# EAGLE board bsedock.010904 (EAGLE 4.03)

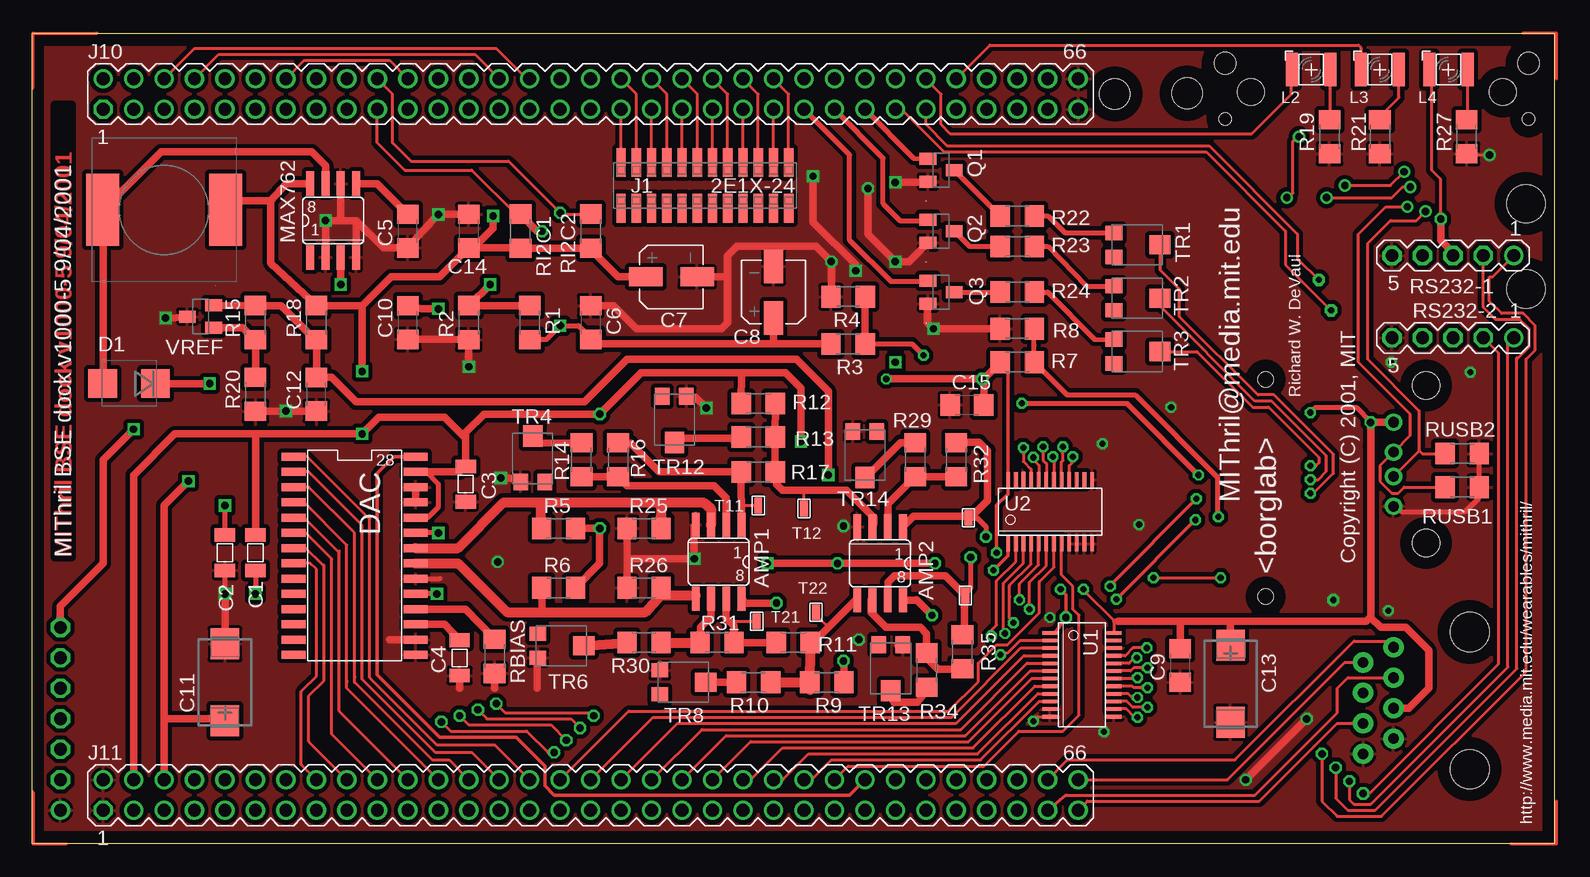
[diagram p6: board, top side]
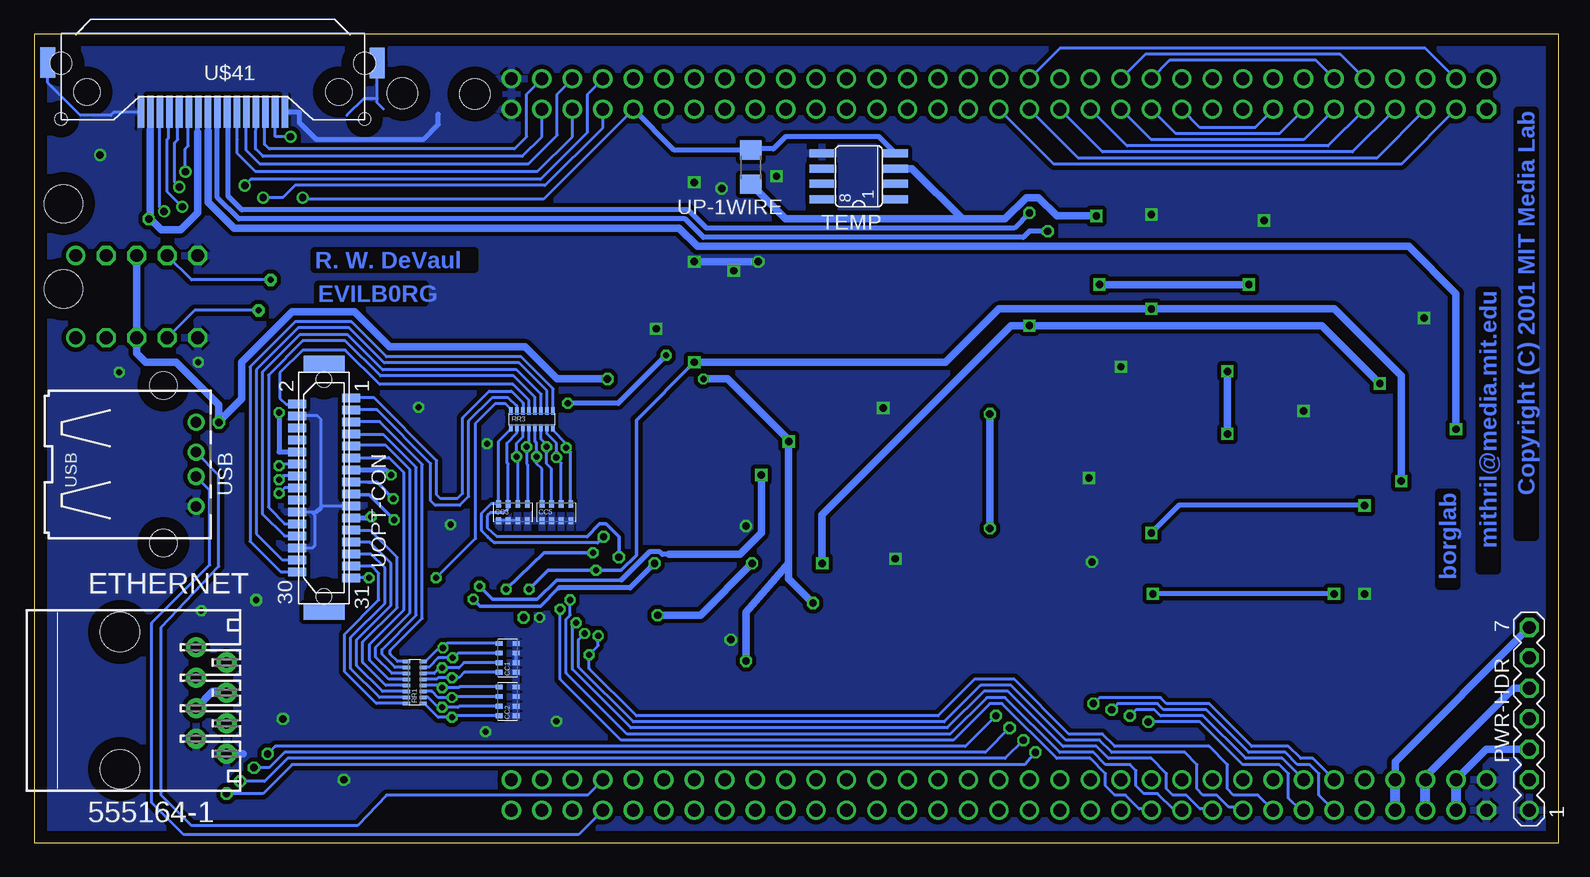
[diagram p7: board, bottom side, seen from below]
Size 126.98 x 67.49 mm. Coordinates in mm from the lower left corner, seen from the top.
Outline: 0,0 126.98,0 126.98,67.49 0,67.49 0,0
Copper layers used: Top, Bottom
Holes 3.17 mm at 124.58,46.19 124.58,53.3
Holes 2.54 mm at 90.29,62.45 96.32,62.51

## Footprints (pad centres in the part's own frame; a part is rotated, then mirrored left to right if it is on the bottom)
SO08 = smd 0.66 x 2.032: 1 -1.905,-3.073; 2 -0.635,-3.073; 3 0.635,-3.073; 4 1.905,-3.073; 5 1.905,3.073; 6 0.635,3.073; 7 -0.635,3.073; 8 -1.905,3.073
1206 = smd 1.143 x 1.702: 1 -1.473,0; 2 1.473,0
C1206 = smd 1.6 x 1.8: 1 -1.4,0; 2 1.4,0
PAN-LY-C = smd 1.6 x 2.8: P+ 0,-2.15; P- 0,2.15
CT7343 = smd 2.6 x 2.4: 1 -3.2,0; 2 3.2,0
ECJRV = smd 0.4 x 0.6: P$1 -1.2,-0.7; P$2 -0.4,-0.7; P$3 0.4,-0.7; P$4 1.2,-0.7; P$5 1.2,0.7; P$6 0.4,0.7; P$7 -0.4,0.7; P$8 -1.2,0.7
SMB = smd 2.4 x 2.4: 1 -2.2,0; 2 2.2,0
SMD-28 = smd 0.66 x 2.007: 1 -8.89,-5.08; 2 -7.62,-5.08; 3 -6.35,-5.08; 4 -5.08,-5.08; 5 -3.81,-5.08; 6 -2.54,-5.08; 7 -1.27,-5.08; 8 0,-5.08; 9 1.27,-5.08; 10 2.54,-5.08; 11 3.81,-5.08; 12 5.08,-5.08; 13 6.35,-5.08; 14 7.62,-5.08; 15 7.62,5.08; 16 6.35,5.08; 17 5.08,5.08; 18 3.81,5.08; 19 2.54,5.08; 20 1.27,5.08; 21 0,5.08; 22 -1.27,5.08; 23 -2.54,5.08; 24 -3.81,5.08; 25 -5.08,5.08; 26 -6.35,5.08; 27 -7.62,5.08; 28 -8.89,5.08
555164-1 = drill 0.889 pad 1.676 round: 1 -4.445,5.207; 2 -3.175,7.747; 3 -1.905,5.207; 4 -0.635,7.747; 5 0.635,5.207; 6 1.905,7.747; 7 3.175,5.207; 8 4.445,7.747 | hole 3.251: -5.715,-1.143; 5.715,-1.143
2E1X-24 = smd 0.762 x 2.388: P$1 -7.62,1.905; P$2 -7.62,-1.905; P$3 -6.35,1.905; P$4 -6.35,-1.905; P$5 -5.08,1.905; P$6 -5.08,-1.905; P$7 -3.81,1.905; P$8 -3.81,-1.905; P$9 -2.54,1.905; P$10 -2.54,-1.905; P$11 -1.27,1.905; P$12 -1.27,-1.905; P$13 0,1.905; P$14 0,-1.905; P$15 1.27,1.905; P$16 1.27,-1.905; P$17 2.54,1.905; P$18 2.54,-1.905; P$19 3.81,1.905; P$20 3.81,-1.905; P$21 5.08,1.905; P$22 5.08,-1.905; P$23 6.35,1.905; P$24 6.35,-1.905
BSEHDR = drill 1.067 pad 1.6 octagon: 1 -41.91,-1.27 | drill 1.067 pad 1.6 round: 2 -41.91,1.27; 3 -39.37,-1.27; 4 -39.37,1.27; 5 -36.83,-1.27; 6 -36.83,1.27; 7 -34.29,-1.27; 8 -34.29,1.27; 9 -31.75,-1.27; 10 -31.75,1.27; 11 -29.21,-1.27; 12 -29.21,1.27; 13 -26.67,-1.27; 14 -26.67,1.27; 15 -24.13,-1.27; 16 -24.13,1.27; 17 -21.59,-1.27; 18 -21.59,1.27; 19 -19.05,-1.27; 20 -19.05,1.27; 21 -16.51,-1.27; 22 -16.51,1.27; 23 -13.97,-1.27; 24 -13.97,1.27; 25 -11.43,-1.27; 26 -11.43,1.27; 27 -8.89,-1.27; 28 -8.89,1.27; 29 -6.35,-1.27; 30 -6.35,1.27; 31 -3.81,-1.27; 32 -3.81,1.27; 33 -1.27,-1.27; 34 -1.27,1.27; 35 1.27,-1.27; 36 1.27,1.27; 37 3.81,-1.27; 38 3.81,1.27; 39 6.35,-1.27; 40 6.35,1.27; 41 8.89,-1.27; 42 8.89,1.27; 43 11.43,-1.27; 44 11.43,1.27; 45 13.97,-1.27; 46 13.97,1.27; 47 16.51,-1.27; 48 16.51,1.27; 49 19.05,-1.27; 50 19.05,1.27; 51 21.59,-1.27; 52 21.59,1.27; 53 24.13,-1.27; 54 24.13,1.27; 55 26.67,-1.27; 56 26.67,1.27; 57 29.21,-1.27; 58 29.21,1.27; 59 31.75,-1.27; 60 31.75,1.27; 61 34.29,-1.27; 62 34.29,1.27; 63 36.83,-1.27; 64 36.83,1.27; 65 39.37,-1.27; 66 39.37,1.27
D124C = smd 2.743 x 5.994: P$1 -5.131,0; P$2 5.131,0
L62711CT = smd 1 x 2.8: P$1 -1.6,0; P$2 1.6,0
MA07-1 = drill 1.067 pad 1.6 round: 1 -7.62,0 | drill 1.067 pad 1.6 octagon: 2 -5.08,0; 3 -2.54,0; 4 0,0; 5 2.54,0; 6 5.08,0; 7 7.62,0
SOT23 = smd 1 x 1.4: 1 -0.95,-1.1; 2 0.95,-1.1; 3 0,1.1
R1206 = smd 1.6 x 1.803: 1 -1.422,0; 2 1.422,0
EXB2HV = smd 0.294 x 0.6: P$1 -1.75,-0.7; P$2 -1.25,-0.7; P$3 -0.75,-0.7; P$4 -0.25,-0.7; P$5 0.25,-0.7; P$6 0.75,-0.7; P$7 1.25,-0.7; P$8 1.75,-0.7; P$9 1.75,0.7; P$10 1.25,0.7; P$11 0.75,0.7; P$12 0.25,0.7; P$13 -0.25,0.7; P$14 -0.75,0.7; P$15 -1.25,0.7; P$16 -1.75,0.7
MA05-1 = drill 1.067 pad 1.6 round: 1 -5.08,0 | drill 1.067 pad 1.6 octagon: 2 -2.54,0; 3 0,0; 4 2.54,0; 5 5.08,0
TEST = smd 0.66 x 1.27: P$1 0,0
P7JSMTPO = smd 1.194 x 1.397: 1 -1,-1.854; 3 1,-1.854 | smd 1.6 x 1.778: 2 0,1.98
QSOP24 = smd 0.305 x 1.27: P$1 0.838,-0.711; P$2 1.473,-0.711; P$3 2.108,-0.711; P$4 2.743,-0.711; P$5 3.378,-0.711; P$6 4.013,-0.711; P$7 4.648,-0.711; P$8 5.283,-0.711; P$9 5.918,-0.711; P$10 6.553,-0.711; P$11 7.188,-0.711; P$12 7.823,-0.711; P$13 7.823,4.623; P$14 7.188,4.623; P$15 6.553,4.623; P$16 5.918,4.623; P$17 5.283,4.623; P$18 4.648,4.623; P$19 4.013,4.623; P$20 3.378,4.623; P$21 2.743,4.623; P$22 2.108,4.648; P$23 1.473,4.623; P$24 0.838,4.623
HRS3500 = smd 0.55 x 2.7: P$1 6,1.35; P$2 5.2,1.35; P$3 4.4,1.35; P$4 3.6,1.35; P$5 2.8,1.35; P$6 2,1.35; P$7 1.2,1.35; P$8 0.4,1.35; P$9 -0.4,1.35; P$10 -1.2,1.35; P$11 -2,1.35; P$12 -2.8,1.35; P$13 -3.6,1.35; P$14 -4.4,1.35; P$15 -5.2,1.35; P$16 -6,1.35 | smd 1.27 x 2.54: P_GND1 -13.7,-2.7; P_GND2 13.76,-2.74 | hole 2.2: -10.5,-0.3; 10.5,-0.3 | hole 1.8: -12.65,-2.7; 12.65,-2.7 | hole 1: -12.65,1.95; 12.65,1.95
DF9-31S = smd 0.7 x 1.5: 1 -7.5,2.25; 2 -7,-2.25; 3 -6.5,2.25; 4 -6,-2.25; 5 -5.5,2.25; 6 -5,-2.25; 7 -4.5,2.25; 8 -4,-2.25; 9 -3.5,2.25; 10 -3,-2.25; 11 -2.5,2.25; 12 -2,-2.25; 13 -1.5,2.25; 14 -1,-2.25; 15 -0.5,2.25; 16 0,-2.25; 17 0.5,2.25; 18 1,-2.25; 19 1.5,2.25; 20 2,-2.25; 21 2.5,2.25; 22 3,-2.25; 23 3.5,2.25; 24 4,-2.25; 25 4.5,2.25; 26 5,-2.25; 27 5.5,2.25; 28 6,-2.25; 29 6.5,2.25; 30 7,-2.25; 31 7.5,2.25 | smd 1.3 x 3.4: M1 -10.35,0; M2 10.35,0 | hole 1.27: 9.05,0; -9.05,0
USB = drill 0.889 pad 1.422 round: 1 -3.505,12.7; 2 -1.016,12.7; 3 1.016,12.7; 4 3.505,12.7 | hole 2.261: -6.566,9.982; 6.566,9.982

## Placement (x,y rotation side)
AMP1  AD8042AR  [SO08]  57.27,23.46 180 top
AMP2  EL2250CS  [SO08]  70.73,23.33 180 top
C1  0.1uF  [1206]  18.66,24.22 90 top
C2  0.1uF  [1206]  16.12,24.22 270 top
C3  0.1uF  [1206]  36.19,29.93 270 top
C4  0.1uF  [1206]  35.68,15.46 270 top
C5  0.1uF  [C1206]  31.36,51.02 90 top
C6  0.1uF  [C1206]  46.6,43.4 270 top
C7  33uF  [PAN-LY-C]  53.34,47.21 270 top
C8  33uF  [PAN-LY-C]  61.84,45.94 0 top
C9  0.1uF  [C1206]  95.75,14.82 90 top
C10  0.1uF  [C1206]  31.36,43.4 90 top
C11  10uF  [CT7343]  16.12,13.42 90 top
C12  0.1uF  [C1206]  23.74,37.43 90 top
C13  10uF  [CT7343]  99.94,13.3 270 top
C14  0.1uF  [C1206]  36.44,51.02 270 top
C15  0.1uF  [C1206]  77.97,36.54 0 top
CC1  10pF  [ECJRV]  87.56,15.46 90 bottom
CC2  10pF  [ECJRV]  87.56,11.84 90 bottom
CC3  10pF  [ECJRV]  87.12,27.58 0 bottom
CC5  10pF  [ECJRV]  83.5,27.58 0 bottom
D1  MBRS130LT3  [SMB]  8.12,38.32 180 top
DAC  THS5641IDW  [SMD-28]  26.92,23.33 270 top
ETHERNET  555164-1  [555164-1]  118.74,11.9 270 bottom
J1  2E1X-24  [2E1X-24]  56.76,54.83 0 top
J10  BSEHDR  [BSEHDR]  47.87,62.45 0 top
J11  BSEHDR  [BSEHDR]  47.87,4.03 0 top
L1  18uH  [D124C]  11.04,52.79 180 top
L2  L628111CT-ND  [L62711CT]  106.67,64.48 0 top
L3  L628111CT-ND  [L62711CT]  112.39,64.48 0 top
L4  L628111CT-ND  [L62711CT]  118.11,64.48 0 top
MAX762  MAX762  [SO08]  25.14,51.91 0 top
PWR-HDR  MA07-1  [MA07-1]  2.41,10.38 90 bottom
Q1  2N7002  [SOT23]  75.81,56.1 270 top
Q2  2N7002  [SOT23]  75.81,51.02 270 top
Q3  2N7002  [SOT23]  75.81,45.94 270 top
R1  1.267M  [R1206]  41.52,43.4 270 top
R2  200K  [R1206]  36.44,43.4 90 top
R3  16.4k  [R1206]  68.07,41.62 180 top
R4  23.6k  [R1206]  68.07,45.55 0 top
R5  2.65k  [R1206]  43.94,26.25 0 top
R6  2.65k  [R1206]  43.94,21.3 0 top
R7  20K  [R1206]  82.16,40.09 180 top
R8  20K  [R1206]  82.16,42.89 0 top
R9  2.52k  [R1206]  66.29,13.42 0 top
R10  2.0k  [R1206]  60.19,13.42 0 top
R11  2.90k  [R1206]  63.49,16.73 180 top
R12  7.06k  [R1206]  60.57,36.66 180 top
R13  2.0k  [R1206]  60.57,33.87 0 top
R14  2k  [R1206]  45.84,31.97 270 top
R15  43k  [R1206]  18.66,43.4 90 top
R16  3.78k  [R1206]  48.89,31.97 90 top
R17  4.05k  [R1206]  60.57,30.95 180 top
R18  47k  [R1206]  23.74,43.4 90 top
R19  2.2k  [R1206]  108.2,58.89 90 top
R20  30k  [R1206]  18.66,37.43 90 top
R21  2.2k  [R1206]  112.39,58.89 90 top
R22  4.7 ohm  [R1206]  82.16,52.29 180 top
R23  4.7 ohm  [R1206]  82.16,49.75 180 top
R24  4.7 ohm  [R1206]  82.16,45.94 180 top
R25  49  [R1206]  51.05,26.25 0 top
R26  49  [R1206]  51.05,21.3 0 top
R27  2.2k  [R1206]  119.63,58.89 90 top
R29  2k  [R1206]  73.66,31.97 270 top
R30  2k  [R1206]  51.05,16.73 0 top
R31  3.78k  [R1206]  57.14,16.73 0 top
R32  6.3k  [R1206]  77.08,31.97 90 top
R34  2k  [R1206]  74.61,14.44 90 top
R35  6.3k  [R1206]  77.59,15.96 90 top
RBIAS  2k  [R1206]  38.6,15.58 90 top
RI2C1  5k  [R1206]  40.76,51.02 270 top
RI2C2  5k  [R1206]  46.6,51.02 270 top
RR1  10  [EXB2HV]  95.31,13.42 90 bottom
RR3  10  [EXB2HV]  85.53,35.33 0 bottom
RS232-1  MA05-1  [MA05-1]  118.49,48.98 180 top
RS232-2  MA05-1  [MA05-1]  118.49,42.13 180 top
RUSB1  15K  [R1206]  119.25,29.68 180 top
RUSB2  15K  [R1206]  119.25,32.47 180 top
T1  TEST  [TEST]  60.57,28.16 0 top
T2  TEST  [TEST]  60.45,18.5 0 top
T3  TEST  [TEST]  65.4,19.27 0 top
T4  TEST  [TEST]  64.38,27.9 0 top
T5  TEST  [TEST]  78.1,27.14 0 top
T6  TEST  [TEST]  77.85,20.66 0 top
TEMP  DS1820  [SO08]  58.29,55.59 90 bottom
TR1  200 POT  [P7JSMTPO]  92.07,49.87 270 top
TR2  200 POT  [P7JSMTPO]  92.07,45.43 270 top
TR3  200 POT  [P7JSMTPO]  92.07,40.98 270 top
TR4  200 POT  [P7JSMTPO]  41.78,31.97 0 top
TR6  200 POT  [P7JSMTPO]  44.06,16.47 270 top
TR8  200 POT  [P7JSMTPO]  54.22,13.42 270 top
TR12  200 POT  [P7JSMTPO]  53.59,35.4 180 top
TR13  200 POT  [P7JSMTPO]  71.62,14.69 180 top
TR14  200 POT  [P7JSMTPO]  69.46,32.47 180 top
U1  74LVX3245QSCF  [QSOP24]  85.59,18.38 270 top
U2  74LVX3245QSCF  [QSOP24]  80.58,25.68 0 top
U$41  HRS3500R  [HRS3500]  112.14,62.32 180 bottom
UOPT-CON  DF9-31S  [DF9-31S]  102.86,29.62 270 bottom
UP-1WIRE  5k  [R1206]  67.31,56.35 270 bottom
USB  USB-87531  [USB]  126.23,31.59 270 bottom
VREF  4041CIM  [SOT23]  14.09,43.9 90 top

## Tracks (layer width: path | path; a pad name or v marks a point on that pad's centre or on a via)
1WIRE  (via drill 0.61 pad 1.02)
  Top 0.254: v105.66,58.89 105.53,58.89 105.15,58.51 105.15,54.19 104.77,53.81 v104.64,53.81
  Bottom 0.254: v105.66,58.89 106.93,58.89 U$41.P$15 | v104.64,53.81 104.77,53.68 84.58,53.68 J10.57
  Bottom 0.406: J10.57 73.68,57.77 UP-1WIRE.1 67.2,57.87 65.4,57.87 64.38,58.89 56.61,58.89 TEMP.4
+2V  (via drill 0.51 pad 0.3, 0.61 pad 1.02)
  Top 0.305: v97.09,28.73 89.91,21.49 v89.91,21.43
  Top 0.61: v66.42,30.7 66.42,37.68 63.75,40.35 49.65,40.35 46.1,36.79 27.05,36.79 25.01,38.82 C12.2 R18.1 23.64,41.97 20.82,44.79 18.66,44.79 | 18.66,44.79 R15.2 | VREF.2 18.66,44.79
  Bottom 0.305: 78.1,21.93 83.5,21.93 85.08,20.35 88.83,20.35 v89.91,21.43 | UOPT-CON.15 99.18,30.09 98.45,30.09 v97.09,28.73
  Bottom 0.406: 74.1,24.09 74.67,24.09 74.86,24.28 75.75,24.28 78.1,21.93
  Bottom 0.61: v66.42,30.7 66.42,25.87 68.19,24.09 74.1,24.09
+3V  (via drill 0.51 pad 0.3, 0.61, 0.61 pad 1.02)
  Top 0.254: 81.4,24.98 U2.P$1
  Top 0.305: U1.P$1 85.33,17.54 v86.23,18.82 86.23,20.73 v85.78,21.17 | v80.19,22.76 81.4,23.96 81.4,24.98
  Top 0.61: J11.6 11.04,10.38 | 11.04,10.38 11.04,28.16 v13.08,30.19 | v33.9,44.54 32.51,44.54 C10.2 | C11.1 16.12,10.38 11.04,10.38
  Bottom 0.305: v85.78,21.17 84.2,22.76 v80.19,22.76 78.1,22.76 76.83,24.03 76.83,35.27 v72,40.09
  Bottom 0.61: v13.08,30.19 13.08,38.95 18.66,44.54 v33.9,44.54 46.6,44.54 51.05,40.09 v72,40.09 | PWR-HDR.5 3.68,12.92 11.04,5.55 J11.6
  Bottom 0.813: J11.5 J11.6
+5V  (via drill 0.51 pad 0.3, 0.61, 0.61 pad 1.02)
  Top 0.254: 116.58,64.4 L4.P$1 116.5,64.02 116.45,63.97 116.45,64.22 116.71,63.97 116.71,56.1 117.47,55.33 v117.47,52.03 | v87.69,21.17 87.69,21.11 90.22,18.58 U1.P$24
  Top 0.305: 81.4,30.32 U2.P$24 | 81.4,30.32 81.4,29.11 80.45,28.16 v80.45,24.22 | 80.77,40.09 80.77,40.22 81.4,39.59 81.4,30.32
  Top 0.406: DAC.24 33.02,27.14 33.9,28.03 33.9,29.93 32.89,30.95 DAC.27 31.87,30.95 | v106.61,35.9 106.99,36.28 110.5,36.28 111.63,35.15 111.64,35.14 | 90.55,18.5 90.29,18.5
  Top 0.61: ETHERNET.5 114.8,11.27 116.45,12.92 116.45,16.09 114.55,18 112.45,18 111.63,18.82 111.63,18.89 | 59.18,39.2 50.8,39.2 v47.37,35.78 37.71,35.78 36.19,34.25 36.19,33.74 | 59.18,39.2 62.86,39.2 64.13,37.94 v64.13,33.49 | 18.66,34.12 v27.55,34.12 28.95,35.52 34.41,35.52 36.19,33.74 | C14.2 34.03,47.21 29.97,47.21 27.55,44.79 | 27.55,44.79 23.74,44.79 | MAX762.8 23.26,54.95 21.2,54.95 19.93,53.56 | C14.2 38.86,49.62 40,49.62 RI2C1.2 RI2C2.2 | R5.2 v47.37,26.25 47.37,23.33 R6.2 | 59.18,39.2 R12.2 | 67.81,12.89 67.81,12.79 | 67.81,12.89 R9.2 | v67.69,15.2 67.81,12.89 | RI2C2.2 46.6,49.62 | 23.74,44.79 R18.2 | 23.74,44.79 19.93,48.35 19.93,53.56 | L1.P$1 16.94,53.56 19.93,53.56 | DAC.27 35.68,30.95 36.19,31.46 C3.1 36.19,33.74 | J11.4 8.5,30.7 11.93,34.12 18.66,34.12 | v27.55,39.33 27.55,44.79 | 18.66,34.12 C1.2 | RI2C2.2 46.6,49.49 48.89,47.21 C7.P+ | v38.48,52.29 38.48,51.27 36.95,49.75 36.44,49.75 C14.2 | v117.47,52.03 117.47,50.25 118.49,49.24 RS232-1.3 | v62.1,20.03 59.3,20.03 59.3,20.28 59.2,20.38 AMP1.8 | R7.2 80.77,40.09 79.37,38.7 v79.24,38.7 | v71.24,38.7 v79.24,38.7 | 111.63,33.11 111.63,18.89 | 111.63,33.11 111.63,33.12 | v111.63,35.08 111.63,34.76 111.63,33.11 | v111.63,35.08 111.63,35.15 | USB.1 v111.63,35.08 | C15.2 79.37,38.57 v79.24,38.7 | 99.94,18.5 C13.1 | 95.75,18.5 C9.2 | 99.94,18.5 111.25,18.5 111.63,18.89 | 95.75,18.5 90.55,18.5 | 99.94,18.5 95.75,18.5
  Bottom 0.254: v64.13,33.49 64.07,33.55
  Bottom 0.305: v80.45,24.22 84.51,24.22 v87.69,21.17
  Bottom 0.406: 117.34,59.45 U$41.P$2 | v117.47,52.03 117.34,52.03 | U$41.P$7 113.38,60.92 113.41,60.92 113.41,59.27 | UOPT-CON.10 106.47,32.62 106.61,32.6 v106.61,35.9
  Bottom 0.61: v64.13,33.49 64.13,23.33 | v27.55,34.12 v27.55,39.33 | v47.37,35.78 v47.37,26.25 | 117.34,59.45 117.34,52.03 116.45,51.14 114.8,51.14 113.41,52.54 113.41,59.27 | v67.69,15.2 67.69,19.27 64.13,23.33 | v38.48,52.29 41.78,52.29 43.3,53.81 44.32,53.81 46.1,52.03 49.65,52.03 | 49.65,52.03 64.38,52.03 67.18,54.83 67.2,54.83 UP-1WIRE.2 | ETHERNET.4 111.12,12.66 112.14,12.66 ETHERNET.5 | RS232-1.3 RS232-2.3 118.49,40.86 117.72,40.09 115.18,40.09 111.63,36.54 111.63,35.14 | 64.13,23.33 64.13,22.06 v62.1,20.03 | TEMP.3 53.84,56.22 49.65,52.03 | J11.4 5.96,7.84 PWR-HDR.3 | v71.24,38.7 69.21,38.7 64.07,33.55 | 111.63,35.14 v111.63,35.08 | v79.24,38.7 83.43,38.7 86.1,41.36 97.4,41.36 100.33,44.29 105.53,44.29 109.72,40.09 109.72,37.05 111.63,35.14
  Bottom 0.813: J11.4 J11.3
+6.5VREF  (via drill 0.51 pad 0.3)
  Top 0.406: R3.1 73.4,41.62 v74.35,40.67 | v82.55,36.66 91.31,36.66 v97.28,30.7
  Top 0.61: R3.1 R4.2
  Bottom 0.406: 74.29,40.73 v74.35,40.67 78.35,36.66 v82.55,36.66 | UOPT-CON.13 100.58,31.08 97.66,31.08 v97.28,30.7
+11V  (via drill 0.51 pad 0.3, 0.61, 0.61 pad 1.02)
  Top 0.305: v90.42,20.35 v97.02,26.95
  Top 0.406: C6.2 46.6,42.13 45.59,43.14 v44.06,43.14 42.9,41.97 R1.2
  Top 0.61: D1.1 v14.85,38.32 | 61.84,41.62 C8.P+ | 61.84,41.62 R3.2 | C6.2 46.98,41.62 61.84,41.62 | v75.31,23.33 v67.18,23.33 v61.34,23.33 | v75.05,19.01 73.78,20.28 73.76,20.26 AMP2.8
  Bottom 0.305: 83.31,21.3 84.83,19.77 89.85,19.77 v90.42,20.35 | UOPT-CON.17 100.06,29.12 100.07,29.11 100.01,29.05 99.12,29.05 v97.02,26.95
  Bottom 0.406: v75.31,23.33 77.34,21.3 83.31,21.3
  Bottom 0.61: v61.34,23.33 61.34,27.39 45.59,43.14 v44.06,43.14 19.68,43.14 v14.85,38.32 | v75.05,19.01 71.5,19.01 v67.18,23.33
BLINKY1
  Top 0.254: L3.P$1 110.79,66.33 110.61,66.51 79.88,66.51 J10.58
BLINKY2
  Top 0.254: J10.56 75.81,62.45 75.81,59.91 76.58,59.14 101.72,59.14 105.02,62.45 105.02,64.43 L2.P$1
BSE_B
  Top 0.406: Q1.1 73.53,57.09 J10.51
BSE_G
  Top 0.406: Q2.1 74.78,51.91 72.39,51.91 70.99,53.3 70.99,57.11 J10.49
BSE_INIT
  Top 0.254: J11.50 68.07,6.44 79.37,6.44 82.29,9.36 85.97,9.36 87.31,10.69 87.31,19.01 86.8,19.52 86.8,21.43 85.86,22.37 U2.P$8 85.85,24.98
BSE_PDR
  Top 0.254: J11.32 49.78,11.01 76.45,11.01 78.93,13.49 78.93,15.01 80.45,16.54 81.34,16.54 84,19.2 84,19.84 | 85.21,24.98 U2.P$7 85.22,23.02 84,21.81 84,19.84 | 84,19.84 84,19.9
BSE_R
  Top 0.406: Q3.1 74.78,46.83 71.62,46.83 68.19,50.25 68.19,57.37 J10.47
BSEDCIN  (via drill 0.61 pad 1.02)
  Top 0.61: v8.5,34.51 5.96,31.97 5.96,23.33 2.41,19.77 PWR-HDR.7
  Bottom 0.406: 112.52,59.4 112.54,60.94 U$41.P$8
  Bottom 0.61: v8.5,34.51 8.5,45.81 12.44,49.75 71.75,49.75 73.27,51.27 110.36,51.27 112.52,53.43 112.52,59.4 | PWR-HDR.7 13.58,6.82 J11.8
  Bottom 0.813: J11.7 J11.8
DAC0
  Top 0.254: DAC.8 23.24,23.33 23.74,22.82 23.74,13.93 22.47,12.66 22.47,6.57 J11.16
DAC1
  Top 0.254: 24.38,23.08 22.73,24.73 21.97,24.73 DAC.7 | J11.18 23.11,8.47 23.11,12.28 24.38,13.55 24.38,23.08 | 24.38,23.08 24.38,23.2
DAC2
  Top 0.254: J11.20 25.01,9.11 25.01,23.71 22.85,25.87 DAC.6
DAC3
  Top 0.254: 25.65,24.22 22.73,27.14 DAC.5 | 25.65,24.22 25.65,24.35 | J11.22 25.65,11.01 25.65,24.22
DAC4
  Top 0.254: 26.28,13.55 26.28,24.85 22.73,28.41 DAC.4 21.59,28.41 | 26.28,13.55 26.28,13.42 | J11.24 26.28,12.92 26.28,13.55
DAC5
  Top 0.254: J11.26 34.79,6.95 33.4,6.95 26.92,13.42 26.92,13.93 | 26.92,13.93 26.92,25.87 23.11,29.68 21.97,29.68 21.84,29.81 DAC.3 | 26.92,13.93 26.92,13.8
DAC6
  Top 0.254: J11.28 36.7,7.58 33.65,7.58 27.55,13.68 27.55,26.5 23.11,30.95 DAC.2
DAC7
  Top 0.254: J11.30 38.6,8.22 33.78,8.22 28.19,13.8 28.19,27.01 22.98,32.22 DAC.1 21.71,32.22
DAC_CLK
  Top 0.305: J11.52 68.19,4.03 43.56,4.03 42.79,4.79 42.79,6.44 40.38,8.85 34.03,8.85 28.82,14.06 28.82,30.82 30.22,32.22 DAC.28 32.25,32.22
EXP_1  (via drill 0.61 pad 1.02)
  Top 0.254: v107.94,53.81 113.41,53.81 114.3,54.7 v114.93,54.7
  Bottom 0.254: J10.59 79.62,59.65 84.45,54.83 105.28,54.83 106.29,53.81 v107.94,53.81 | v114.93,54.7 115.31,55.08 115.31,58.38 115.06,58.64 115.06,60.85 U$41.P$5
EXP_2  (via drill 0.61 pad 1.02)
  Top 0.254: v109.47,54.83 113.28,54.83 v114.42,55.97
  Bottom 0.254: J10.60 80.89,62.45 80.89,59.27 84.83,55.33 108.96,55.33 v109.47,54.83 | U$41.P$6 114.17,60.92 114.17,58.13 114.42,57.87 v114.42,55.97
EXP_3
  Bottom 0.254: J10.61 82.16,58.89 85.08,55.97 108.58,55.97 110.1,57.49 110.1,58.64 U$41.P$11
EXP_4
  Bottom 0.254: J10.62 83.43,62.45 83.43,59.02 85.85,56.6 108.2,56.6 109.34,57.75 109.34,60.92 U$41.P$12
EXP_5
  Bottom 0.254: J10.63 84.7,58.89 86.36,57.24 107.94,57.24 108.58,57.87 U$41.P$13
EXP_6
  Bottom 0.254: J10.64 85.97,62.45 85.97,58.89 86.99,57.87 107.44,57.87 107.82,58.26 107.82,60.92 U$41.P$14
FEXT0
  Top 0.254: J1.P$1 J10.35
FEXT1
  Top 0.254: J1.P$3 50.41,62.45 J10.36
FEXT2
  Top 0.254: J1.P$5 J10.37
FEXT3
  Top 0.254: J1.P$7 52.95,62.45 J10.38
FEXT4
  Top 0.254: J1.P$9 J10.39
FEXT5
  Top 0.254: J1.P$11 55.49,62.45 J10.40
FEXT6
  Top 0.254: J1.P$13 J10.41
FEXT7
  Top 0.254: J1.P$15 58.03,62.45 J10.42
FEXT8
  Top 0.254: J1.P$17 J10.43
FEXT9
  Top 0.254: J1.P$19 60.57,62.45 J10.44
FEXT10
  Top 0.254: J1.P$21 J10.45
FEXT11
  Top 0.254: J1.P$23 63.11,62.45 J10.46
GND1  (via drill 0.51 pad 0.3, 0.51 pad 1.02, 0.61 pad 1.02)
  Top 0.254: R27.1 119.73,57.37 v121.53,57.37 | U1.P$12 83.87,10.55 v83.5,10.19
  Top 0.406: v16.12,20.79 C2.2 | DAC.20 34.03,22.06 | C3.2 36.19,28.41 | R19.1 108.2,57.49 | R21.1 112.39,57.62 112.26,57.49 | RUSB1.1 RUSB2.1 | RUSB1.1 120.67,29.58 120.52,29.43 | RUSB1.1 120.67,28.82 119.5,27.65 114.17,27.65 113.66,28.16 113.58,28.08 USB.4
  Top 0.61: MAX762.2 v24.51,51.91 25.78,51.91 | 25.78,51.91 MAX762.6 | Q1.2 74.78,55.08 v72,55.08 | 74.65,44.92 Q3.2 74.67,44.92 74.67,43.4 v75.18,42.89 R8.1 | 27.05,51.91 MAX762.4 | MAX762.2 24.51,48.73 | MAX762.2 24.51,50.25 | v101.21,5.3 v106.29,10.38 | AMP1.4 55.24,26.4 v55.24,23.71 49.65,23.71 | VREF.3 12.95,43.86 v11.17,43.78 | TR4.1 40.06,30.44 v39.11,30.44 | TR6.3 42.16,15.42 42.16,12.92 | TR12.1 55.35,37.16 v56.26,36.28 | DAC.25 DAC.26 | 29.84,16.98 DAC.16 | C4.2 35.68,12.92 | 25.78,51.91 27.05,51.91 | R20.1 v21.2,36.03 C12.1 | C14.1 v33.9,52.41 C5.1 | R26.1 49.65,23.71 | 49.65,23.71 R25.1 | v36.44,39.71 R2.1 33.9,42 C10.1 | 46.73,44.67 C6.1 48.51,44.8 50.41,42.89 57.53,42.89 58.03,43.4 58.03,47.21 | 27.05,51.91 29.33,49.62 C5.1 | RBIAS.1 38.6,12.92 | 16.12,16.6 C11.2 v16.12,20.79 | 58.03,47.21 C7.P- | 58.03,47.21 58.03,48.98 58.8,49.75 61.84,49.75 | R4.1 66.67,45.55 v66.67,48.48 65.4,49.75 61.84,49.75 | 61.84,49.75 C8.P- | v65.15,55.59 65.15,51.78 68.7,48.22 v68.7,47.71 | Q2.2 73.12,48.48 v72,48.48 69.72,50.76 v69.72,54.57 | TR13.1 72.24,16.49 | AMP2.4 68.83,27.01
  Bottom 0.254: U$41.P_GND1 98.44,61.7 97.91,61.18 | U$41.P_GND2 125.9,63.38 123.19,60.67 120.64,60.67 120.39,60.92 118.18,60.92 U$41.P$1 | 106.04,60.87 105.99,60.92 | 100.96,60.67 99.56,62.06 98.42,62.06 | 110.1,7.33 110.61,7.33 110.87,7.58 ETHERNET.8 111.12,7.33 | UOPT-CON.4 103.4,35.62 103.12,35.33 103.12,28.09 | 103.12,28.09 103.12,27.9 103.44,27.58 103.88,27.58 | UOPT-CON.19 100.64,28.09 103.12,28.09 | 103.12,28.09 103.63,27.58 103.88,27.58 | 103.88,27.58 105.09,27.58 105.09,27.59 UOPT-CON.20 105.08,27.58 103.88,27.58 | 103.88,27.58 103.63,27.33 103.63,24.79 103.82,24.6 105.1,24.6 UOPT-CON.26 | CC3.P$1 | CC3.P$1 | CC3.P$2 87.56,26.89 | 87.56,26.89 CC3.P$1 | CC3.P$3 87.56,26.89 | CC1.P$2 86.86,15.01 | CC1.P$2 | CC1.P$3 CC1.P$2
  Bottom 0.406: v24.51,51.91 24.76,51.65 24.76,51.91 | U$41.P$1 118.06,60.97 | U$41.P$16 106.04,60.87 106.04,60.92 104.9,60.92 104.9,60.03 103.5,58.64 94.61,58.64 93.34,59.91 93.34,60.8
  Bottom 0.61: 109.6,7.46 ETHERNET.8 | v66.67,48.48 v72,48.48
  other vias: 108.52,20.28 68.96,16.98 67.69,26.44 38.86,23.46 84.89,18.82 94.99,36.35 119.95,39.27 113.34,40.09 113.09,19.39 92.32,26.57 89.28,33.3 89.4,9.3
  pour Bottom (isolate 0.356): 0,67.4 127,67.4 127,0.09 0,0.09
  pour Top (isolate 0.356): 0,67.65 127,67.65 127,0.22 0,0.22
HCK
  Bottom 0.254: RR1.P$14 97.99,12.67 100.14,14.82 100.14,16.98 97.28,19.84 97.28,23.33 99.05,25.11 100.07,25.11
  Bottom 0.305: 100.07,25.11 100.06,25.12 UOPT-CON.25
HLTOR
  Bottom 0.254: 100.02,32.09 97.47,32.09 97.47,32.16 96.2,30.89 96.2,19.46 99.05,16.6 99.05,15.27 97.47,13.68 RR1.P$12
  Bottom 0.305: 100.02,32.09 UOPT-CON.11
HODL
  Bottom 0.254: RR1.P$11 97.2,14.17 98.55,15.52 98.55,16.34 95.69,19.2 95.69,31.14 97.72,33.17 100.07,33.17 100.04,33.14 UOPT-CON.9
HPL
  Bottom 0.254: RR1.P$13 97.72,13.17 99.63,15.08 | 100.07,26.06 98.99,26.06 96.77,23.84 96.77,19.65 99.63,16.79 99.63,15.08 | 99.63,15.08 99.63,15.01
  Bottom 0.305: 100.07,26.06 100.04,26.09 UOPT-CON.23
HSYNC
  Top 0.254: J10.22 29.84,65.24 22.73,65.24 J10.14
I2CSCL  (via drill 0.61 pad 1.02)
  Top 0.254: RI2C2.1 45.46,52.41 44.19,52.41 v44.06,52.54 39.75,56.86 31.62,56.86 30.09,58.38 30.09,62.45 J10.20
  Bottom 0.406: U$41.P$10 110.94,60.87 110.87,60.8 110.87,53.94 109.72,52.79 72.51,52.79 70.99,51.27 45.33,51.27 v44.06,52.54
I2CSDA  (via drill 0.61 pad 1.02)
  Top 0.254: RI2C1.1 40.38,52.41 36.7,56.1 31.11,56.1 28.82,58.38 J10.19
  Top 0.61: RI2C1.1 40.89,52.29 42.16,51.02 v42.54,51.02
  Bottom 0.406: v42.54,51.02 44.06,51.02 44.57,50.51 71.24,50.51 72.77,52.03 109.98,52.03 111.75,53.81 111.75,60.8 111.74,60.9 U$41.P$9
I_HCK  (via drill 0.51 pad 0.3)
  Top 0.254: U1.P$16 91.45,12.46 91.75,12.15 v92.2,12.15
  Bottom 0.254: RR1.P$3 93.86,12.67 93.34,12.15 v92.2,12.15 92.2,12.22 92.18,12.24 CC2.P$6
I_HLTOR  (via drill 0.51 pad 0.3)
  Top 0.254: U1.P$18 92.12,13.73 v92.2,13.8
  Bottom 0.254: RR1.P$5 93.47,13.68 93.34,13.8 v92.2,13.8 91.63,13.8 91.17,14.26 CC1.P$8
I_HODL  (via drill 0.51 pad 0.3)
  Top 0.254: U1.P$19 90.28,14.36 90.29,14.38 91.63,14.38 91.88,14.63 v93.02,14.63
  Bottom 0.254: RR1.P$6 93.67,14.17 93.21,14.63 93.09,14.63 | 93.09,14.63 v93.02,14.63 91.63,14.63 91.2,15.06 CC1.P$7 | 93.09,14.63 93.15,14.63
I_HPL  (via drill 0.51 pad 0.3)
  Top 0.254: v93.02,12.98 91.88,12.98 91.75,13.11 90.29,13.11 90.28,13.09 U1.P$17
  Bottom 0.254: RR1.P$4 93.22,13.17 v93.02,12.98 91.63,12.98 91.57,13.04 CC2.P$5
I_INIT  (via drill 0.51 pad 0.3)
  Top 0.254: U2.P$16 86.5,30.24 86.48,30.25 86.48,30.29 U2.P$16 | U2.P$16 86.5,31.47 86.8,31.78 v86.8,32.22
  Bottom 0.254: RR3.P$3 86.28,33.88 86.8,33.36 v86.8,32.22 86.72,32.2 CC3.P$6
I_PDR  (via drill 0.51 pad 0.3)
  Top 0.254: v85.97,33.05 85.97,31.9 85.85,31.78 85.85,30.32 U2.P$17 85.86,30.24
  Bottom 0.254: RR3.P$4 85.78,33.24 v85.97,33.05 85.97,31.65 85.92,31.59 CC3.P$5
I_RENE  (via drill 0.51 pad 0.3)
  Top 0.254: U1.P$15 91.32,11.82 91.82,11.33 v93.02,11.33
  Bottom 0.254: RR1.P$2 94.19,12.17 93.34,11.33 v93.02,11.33 91.69,11.33 91.58,11.44 CC2.P$7
I_RENO  (via drill 0.51 pad 0.3)
  Top 0.254: v92.2,10.5 91.94,10.5 91.25,11.2 90.23,11.2 U1.P$14
  Bottom 0.254: RR1.P$1 94.51,11.67 93.34,10.5 v92.2,10.5 92.13,10.5 92,10.64 CC2.P$8
I_TEST1  (via drill 0.51 pad 0.3)
  Top 0.254: U2.P$21 83.32,31.19 82.67,31.84 v82.67,32.98 | U2.P$21 83.32,30.24 83.31,30.25 83.31,30.29 U2.P$21
  Bottom 0.254: RR3.P$8 83.78,34.41 82.67,33.3 v82.67,32.98 82.3,32.61 CC5.P$5
I_TEST2  (via drill 0.51 pad 0.3)
  Top 0.254: U2.P$20 83.95,31.51 83.5,31.97 v83.5,32.16 | U2.P$20 83.95,30.24 83.94,30.25 83.94,30.29 U2.P$20
  Bottom 0.254: RR3.P$7 84.26,34.63 84.26,34.12 83.5,33.36 v83.5,32.16 83.5,32.09 83.1,31.69 CC5.P$6
I_TEST3  (via drill 0.51 pad 0.3)
  Top 0.254: 84.59,30.24 U2.P$19 84.58,30.32 84.58,31.65 84.32,31.9 v84.32,33.05
  Bottom 0.254: RR3.P$6 84.78,33.69 84.32,33.24 84.32,33.11 | 84.32,33.11 v84.32,33.05 84.32,31.65 83.9,31.22 CC5.P$7 | 84.32,33.11 84.32,33.17
I_TEST4  (via drill 0.51 pad 0.3)
  Top 0.254: U2.P$18 85.22,32.14 v85.15,32.22 | U2.P$18 85.22,30.24 85.21,30.25 85.21,30.29 U2.P$18
  Bottom 0.254: RR3.P$5 85.28,33.49 85.15,33.36 v85.15,32.22 85.15,31.65 84.7,31.2 CC5.P$8
I_VCK  (via drill 0.51 pad 0.3)
  Top 0.254: U1.P$21 91.17,15.63 91.82,16.28 v92.96,16.28
  Bottom 0.254: RR1.P$8 94.38,15.17 93.28,16.28 v92.96,16.28 92.58,16.66 CC1.P$5
I_VPL  (via drill 0.51 pad 0.3)
  Top 0.254: U1.P$20 91.49,15 91.94,15.46 v92.13,15.46
  Bottom 0.254: RR1.P$7 94.61,14.69 94.1,14.69 93.34,15.46 v92.13,15.46 92.07,15.46 91.67,15.86 CC1.P$6
INIT
  Bottom 0.254: UOPT-CON.1 98.68,37.12 93.47,31.9 93.47,29.05 93.15,28.73 91.75,28.73 91.31,29.17 91.31,35.46 89.08,37.68 87.24,37.68 86.28,36.72 RR3.P$14
IOUT1
  Top 0.61: 42.41,26.28 R5.1
  Top 0.813: DAC.22 35.55,24.6 39.37,28.41 42.41,28.41 | 42.41,28.41 52.45,28.41 | 52.45,28.41 56,28.41 56.64,27.9 AMP1.3 | 42.41,28.41 42.41,26.28 | R25.2 52.47,27.29 52.45,28.41
IOUT2
  Top 0.406: AMP1.5 55.27,20.38 55.11,20.54 55.24,20.66 55.37,20.66
  Top 0.61: 42.54,19.27 R6.1
  Top 0.813: DAC.21 35.55,23.33 39.62,19.27 42.54,19.27 51.18,19.27 52.45,20.66 | 52.45,20.66 55.37,20.66 | 52.45,20.66 R26.2
K_HCK
  Top 0.254: J11.44 59.94,5.3 62.61,7.96 78.48,7.96 83.62,13.11 84.74,13.11 U1.P$8
K_HLTOR
  Top 0.254: J11.40 57.91,8.98 77.85,8.98 83.24,14.38 U1.P$6
K_HODL
  Top 0.254: J11.38 55.88,9.49 77.47,9.49 82.99,15.01 84.55,15.01 U1.P$5
K_HPL
  Top 0.254: J11.42 59.94,8.47 78.1,8.47 83.37,13.74 85,13.74 U1.P$7
K_LEDB  (via drill 0.51 pad 0.3)
  Top 0.254: 94.1,49.82 94.1,47.78 95.69,46.19 95.69,43.9 102.23,37.36 103.56,37.36 108.52,32.41 108.52,30.82 106.86,29.17 v106.61,29.17
  Top 0.406: 94.1,49.82 TR1.2
  Bottom 0.254: 105.09,29.62 UOPT-CON.16 106.17,29.62 v106.61,29.17
K_LEDG  (via drill 0.51 pad 0.3)
  Top 0.254: TR2.2 94.05,44.78 101.98,36.85 103.37,36.85 107.94,32.28 107.94,31.01 107.25,30.32 v106.61,30.32
  Bottom 0.254: UOPT-CON.14 106.31,30.62 v106.61,30.32
K_LEDR  (via drill 0.51 pad 0.3)
  Top 0.254: v106.61,31.46 107.06,31.46 107.31,31.71 107.31,32.16 103.12,36.35 101.79,36.35 97.15,40.98 TR3.2
  Bottom 0.254: UOPT-CON.12 106.45,31.62 v106.61,31.46
K_RENE
  Top 0.254: J11.46 62.61,5.3 64.77,7.46 78.86,7.46 83.88,12.47 85.02,12.47 84.91,12.46 U1.P$9
K_RENO
  Top 0.254: J11.48 65.02,5.3 66.67,6.95 79.12,6.95 84,11.84 85.02,11.84 84.91,11.82 U1.P$10
K_TEST1  (via drill 0.51 pad 0.3)
  Top 0.254: v81.15,17.49 81.02,17.61 81.02,21.68 82.67,23.33 82.67,24.96 U2.P$3
  Bottom 0.254: J11.17 26.54,3.01 27.43,3.01 28.44,4.03 29.59,4.03 30.09,4.53 30.09,6.57 31.11,7.58 37.21,7.58 38.22,8.6 41.02,8.6 45.59,13.17 48.13,13.17 51.18,10.12 77.08,10.12 81.66,14.69 81.66,16.98 v81.15,17.49
K_TEST2  (via drill 0.51 pad 0.3)
  Top 0.254: v81.85,18.38 81.53,18.76 81.53,20.54 | U2.P$4 83.31,24.96 83.31,23.27 81.53,21.49 81.53,20.54 | 81.53,20.54 81.53,20.6
  Bottom 0.254: J11.19 28.95,2.88 29.84,2.88 30.98,4.03 32.13,4.03 32.63,4.53 32.63,5.8 33.9,7.07 37.46,7.07 38.48,8.09 41.27,8.09 45.84,12.66 47.87,12.66 50.92,9.61 77.28,9.61 82.16,14.5 82.16,18.06 v81.85,18.38
K_TEST3  (via drill 0.51 pad 0.3)
  Top 0.254: U2.P$5 83.95,25.03 83.94,25.04 83.94,23.2 82.36,21.62 v82.36,20.28
  Bottom 0.254: J11.21 32,2.76 33.4,4.15 34.54,4.15 35.17,4.79 35.17,6.06 35.68,6.57 37.71,6.57 38.73,7.58 41.52,7.58 46.1,12.15 47.62,12.15 50.67,9.11 77.59,9.11 82.67,14.19 82.67,18.69 82.36,19.01 v82.36,20.28
K_TEST4  (via drill 0.51 pad 0.3)
  Top 0.254: 84.58,24.98 U2.P$6 84.59,23.15 83.18,21.74 v83.18,19.52
  Bottom 0.254: J11.23 33.78,2.88 34.92,2.88 36.06,4.03 36.95,4.03 37.71,4.79 37.71,5.8 38.98,7.07 41.78,7.07 46.35,11.65 47.37,11.65 50.41,8.6 78.1,8.6 83.18,13.68 v83.18,19.52
K_VCK
  Top 0.254: J11.34 51.81,10.5 76.7,10.5 82.48,16.28 84.89,16.28 U1.P$3
K_VIDH  (via drill 0.61)
  Top 0.406: 77.78,20.79 78.29,21.3 v78.29,23.84
  Top 0.61: 77.78,20.73 77.78,20.79 | R35.2 77.78,17.58 77.78,20.73 | AMP2.7 71.37,21.74 71.94,22.31 76.19,22.31 77.78,20.73 | 77.78,20.73 T6.P$1
  Bottom 0.254: RR3.P$2 86.78,34.21 87.62,33.36 87.62,31.71 87.52,31.6 CC3.P$7 87.52,27.95 87.88,27.58 88.96,27.58 89.21,27.33 89.21,26.25 88.45,25.55 80.96,25.55
  Bottom 0.305: v78.29,23.84 78.29,25.55 79.37,26.63 79.88,26.63 80.96,25.55
K_VIDL  (via drill 0.61)
  Top 0.406: T5.P$1 78.8,27.14 79.56,26.38 v79.56,25.55
  Top 0.61: 78.16,27.2 78.16,27.27 73.5,27.27 AMP2.1 | R32.2 77.12,33.43 78.99,33.43 79.69,32.73 79.69,28.54 78.35,27.2 78.16,27.2 | 78.16,27.2 T5.P$1
  Bottom 0.254: RR3.P$1 87.28,34.53 88.32,33.5 88.32,28.34 88.9,28.34 89.72,27.52 89.72,26.06 89.21,25.55 88.64,25.04 80.07,25.04
  Bottom 0.305: 88.32,28.35 88.32,28.34 CC3.P$8 | v79.56,25.55 80.07,25.04
K_VPL
  Top 0.254: J11.36 53.84,9.99 77.08,9.99 82.74,15.65 U1.P$4
K_VREF  (via drill 0.51 pad 0.3)
  Top 0.406: R7.1 83.56,41.49 R8.2 | R7.1 83.56,40.09 | R7.1 86.32,37.36 92.01,37.36 98.86,30.51 98.86,27.27 v98.93,27.2
  Bottom 0.406: 100.66,27.08 100.71,27.08 | 100.66,27.08 UOPT-CON.21 | v98.93,27.2 99.05,27.08 100.66,27.08
LCD_AC
  Bottom 0.254: J10.24 32.38,65.24 20.19,65.24 J10.12
LCDCLK
  Bottom 0.254: J10.21 29.84,59.65 25.27,59.65 J10.15
LD0
  Bottom 0.254: J10.33 42.03,56.6 13.08,56.6 J10.3
LD1
  Bottom 0.254: J10.4 11.04,66.26 41.52,66.26 J10.32
LD2
  Bottom 0.254: J10.31 40,57.11 15.11,57.11 J10.5
LD3
  Top 0.254: J10.6 13.58,66.26 38.73,66.26 41.27,63.72
  Top 0.406: 41.27,63.72 J10.30
LD4
  Bottom 0.254: J10.7 17.14,57.62 37.97,57.62 J10.29
LD5
  Top 0.254: J10.28 36.95,65.75 15.62,65.75 J10.8
LD6
  Bottom 0.254: J10.27 35.94,58.13 19.17,58.13 J10.9
LD7
  Bottom 0.254: J10.10 18.16,65.75 34.41,65.75 J10.26
LD8
  Bottom 0.254: J10.11 21.2,58.64 33.9,58.64 J10.25
N$1
  Top 0.61: TR4.2 42.41,33.36 R14.1
N$2
  Top 0.406: TR1.1 90.23,50.89 86.13,50.89 84.7,52.29 R22.1
N$3
  Top 0.406: TR2.1 87.91,46.44 84.7,49.75 R23.1
N$4
  Top 0.406: TR3.1 88.58,42 84.7,45.94 R24.1
N$5  (via drill 0.61 pad 1.02)
  Top 0.406: v33.78,20.79 DAC.19 | C1.1 v18.66,20.79
  Bottom 0.406: v18.66,20.79 v33.78,20.79
N$6
  Top 0.406: R22.2 Q1.3
N$7  (via drill 0.61 pad 1.02)
  Top 0.406: C2.1 v16.12,28.16 | v33.9,25.87 DAC.23
  Bottom 0.406: v16.12,28.16 31.62,28.16 v33.9,25.87
N$8
  Top 0.61: R32.1 R29.2 73.63,30.54 71.37,28.28 AMP2.2
N$9
  Top 0.254: 0.12,62.95 0.12,67.53 5.46,67.53
N$10
  Top 0.254: 124.33,67.53 127.12,67.53 127.12,63.72
N$11
  Top 0.813: TR6.2 R30.1
N$12
  Top 0.61: AMP1.2 57.91,28.79 56.89,29.81 49.63,29.81 R16.1 R14.2
N$13
  Top 0.61: TR8.2 R10.1
N$14
  Top 0.61: DAC.17 34.41,18.25 C4.1
N$15
  Top 0.61: AMP2.6 70,20.26 69.97,20.28 69.97,19.27 71.24,18 74.1,18 74.61,17.49 R34.2 74.61,15.46 75.56,14.5 77.59,14.5 R35.1
N$16
  Top 0.61: R13.1 58.54,33.49 58.8,33.74 53.92,33.74 TR12.2
N$17
  Top 0.61: DAC.18 36.19,19.52 RBIAS.2
N$18
  Top 0.61: TR14.2 69.46,30.44 72.41,33.39 R29.1
N$19
  Top 0.61: TR13.2 71.88,11.77 73.85,11.77 74.61,12.66 R34.1
N$20
  Top 0.61: AMP1.6 56.64,18.89 55.75,18 55.75,16.6 R31.1
  Top 0.813: R30.2 R31.1
N$21
  Top 0.61: 18.66,42 R15.1 18.66,41.87 | 18.66,41.87 R20.2 | VREF.1 17.58,42.95 18.66,41.87
N$22
  Top 0.254: 127.12,3.52 127.12,-0.04 123.31,-0.04
N$23
  Top 0.254: 2.92,-0.04 0.12,-0.04 0.12,4.28
N$26
  Top 0.254: R19.2 108.2,60.41 108.28,60.49 L2.P$2
N$27
  Top 0.254: L3.P$2 113.99,62.14 112.26,60.41
  Top 0.406: R21.2 112.39,60.41 112.26,60.41
N$28
  Top 0.254: R27.2 119.63,60.41 119.7,60.49 L4.P$2
N$36  (via drill 0.61 pad 1.02)
  Top 0.61: v25.78,46.57 MAX762.3 | R1.1 R2.2 v38.22,46.57
  Bottom 0.61: v25.78,46.57 v38.22,46.57
N$37
  Top 0.61: 5.96,52.79 L1.P$2 | 5.96,52.79 10.79,57.62 23.36,57.62 24.51,56.48 MAX762.7 | D1.2 5.96,38.27 5.96,52.79
N$38
  Top 0.61: MAX762.5 27.05,54.95 28.82,54.95 C5.2
N$47
  Top 0.406: Q2.3 78.18,49.75 R23.2
N$49
  Top 0.406: Q3.3 R24.2
PDR
  Bottom 0.254: RR3.P$13 85.78,36.91 87.12,38.25 98.23,38.25 101.09,41.11 104.64,41.11 106.55,39.2 106.55,37.11 106.04,36.6 105.34,36.6 105.29,36.62 UOPT-CON.2
RENE
  Bottom 0.254: RR1.P$15 98.25,12.17 100.64,14.57 100.64,17.17 97.78,20.03 97.78,22.95 98.93,24.09 100.07,24.09
  Bottom 0.305: 100.07,24.09 100.05,24.12 UOPT-CON.27
RENO
  Bottom 0.254: RR1.P$16 98.51,11.67 101.15,14.31 101.15,17.42 98.29,20.28 98.29,22.5 98.86,23.08 | 98.86,23.08 100.01,23.08 | 98.86,23.08 98.8,23.08
  Bottom 0.305: 100.05,23.12 100.07,23.14 | 100.05,23.12 UOPT-CON.29 | 100.01,23.08 100.05,23.12
RSRX1  (via drill 0.61)
  Top 0.254: RS232-1.1 121.79,47.21 121.53,47.21 121.53,45.17 122.55,44.16 124.33,44.16 125.34,43.14 125.34,41.11 124.58,40.35 124.58,14.31 112.52,2.25 108.83,2.25 107.56,3.52 v107.56,7.46 | v46.86,10.63 46.73,10.63 46.48,10.88 39.49,10.88 v38.73,11.65
  Bottom 0.254: v107.56,7.46 106.93,8.09 49.4,8.09 v46.86,10.63 | v38.73,11.65 38.22,12.15 33.14,12.15 32.63,11.65 29.08,11.65 25.52,8.09 22.47,8.09 21.46,7.07 20.44,7.07 J11.12
RSRX2  (via drill 0.61)
  Top 0.254: RS232-2.1 123.06,41.62 123.06,14.69 111.63,3.26 110.23,3.26 109.85,3.64 v109.85,5.17 | v44.57,8.6 43.3,9.87 36.44,9.87 v35.68,10.63
  Bottom 0.254: v109.85,5.17 107.82,5.17 105.91,7.07 46.1,7.07 v44.57,8.6 | v35.68,10.63 35.17,11.14 33.65,11.14 33.14,10.63 29.59,10.63 26.03,7.07 22.98,7.07 J11.14
RSTX1  (via drill 0.61)
  Top 0.254: RS232-1.2 121.03,44.67 122.04,43.65 124.07,43.65 124.84,42.89 124.84,41.36 123.95,40.48 123.82,40.48 123.82,14.57 112.01,2.76 109.72,2.76 108.71,3.77 v108.71,6.31 | v45.71,9.61 44.95,10.38 37.97,10.38 v37.21,11.14
  Bottom 0.254: v108.71,6.31 107.44,6.31 106.17,7.58 47.75,7.58 v45.71,9.61 | v37.21,11.14 36.7,11.65 33.4,11.65 32.89,11.14 29.33,11.14 25.78,7.58 22.73,7.58 21.71,6.57 20.7,6.57 19.93,5.8 19.93,4.03 J11.11 18.66,2.63
RSTX2  (via drill 0.61)
  Top 0.254: RS232-2.2 122.3,40.86 122.3,14.95 111.5,4.15 v110.99,4.15 | v43.56,7.58 43.05,7.58 41.27,9.36 34.92,9.36 v34.16,10.12
  Bottom 0.254: v110.99,4.15 107.94,4.15 105.53,6.57 44.45,6.57 v43.56,7.58 | v34.16,10.12 29.84,10.12 26.28,6.57 23.24,6.57 22.47,5.8 22.47,3.77 21.46,2.76 J11.13
RX+
  Top 0.254: J11.63 86.23,4.03 101.98,4.03 108.83,10.88 108.83,12.92 109.72,13.8 ETHERNET.3
RX-
  Top 0.254: J11.65 88.01,3.52 102.36,3.52 108.83,9.99 ETHERNET.6
SENSE1  (via drill 0.51 pad 1.02)
  Top 0.254: v107.31,46.95 105.53,48.73 105.53,50.76 98.17,58.13 76.32,58.13 74.54,59.91 J10.55
  Bottom 0.254: v107.31,46.95 113.91,46.95 RS232-1.4
SENSE2  (via drill 0.51 pad 1.02)
  Top 0.254: J10.53 72.51,61.18 76.07,57.62 97.91,57.62 104.52,51.02 104.52,48.22 v108.33,44.41
  Bottom 0.254: v108.33,44.41 113.66,44.41 RS232-2.4
TEST1
  Bottom 0.254: UOPT-CON.30 106.47,22.62 109.03,25.17 109.03,39.71 105.28,43.46 100.58,43.46 97.66,40.54 86.42,40.54 83.75,37.87 83.75,36.03 RR3.P$9
TEST2
  Bottom 0.254: RR3.P$10 84.28,37.7 86.61,40.03 97.85,40.03 100.77,42.95 105.02,42.95 108.52,39.46 108.52,25.81 106.36,23.65 105.15,23.65 UOPT-CON.28 | UOPT-CON.28 105.09,23.58 | UOPT-CON.28
TEST3
  Bottom 0.254: UOPT-CON.24 106.17,25.62 108.01,27.46 108.01,39.27 104.9,42.38 100.9,42.38 97.97,39.46 86.8,39.46 84.77,37.43 84.77,36.03 RR3.P$11
TEST4
  Bottom 0.254: RR3.P$12 85.28,37.18 87.05,38.95 98.17,38.95 101.09,41.87 104.64,41.87 107.5,39.01 107.5,28.03 106.17,26.63 105.02,26.63 105.04,26.62 UOPT-CON.22
TX+
  Top 0.254: J11.64 86.36,6.95 100.33,6.95 110.23,16.85 113.03,16.85 ETHERNET.1
TX-
  Top 0.254: ETHERNET.2 109.47,15.08 99.69,5.3 J11.66
TX/RX  (via drill 0.51 pad 0.3)
  Top 0.254: v80.77,15.71 80.96,15.9 81.4,15.9 82.42,16.92 U1.P$2 | v80,17.3 80,17.74 80.45,18.19 80.45,21.87 82.05,23.47 U2.P$2
  Bottom 0.254: J11.15 25.01,4.03 27.05,4.03 27.55,4.53 27.55,6.57 29.08,8.09 36.95,8.09 37.97,9.11 40.76,9.11 45.33,13.68 48.64,13.68 51.68,10.63 76.83,10.63 80.77,14.57 v80.77,15.71 80,16.47 v80,17.3
USBD+  (via drill 0.61 pad 1.02)
  Top 0.254: USB.3 115.69,32.73 | 115.69,32.73 115.69,36.03 111.37,40.35 111.37,50 113.28,51.91 115.44,51.91 v116.2,52.67 | RUSB2.2 115.95,32.47 115.69,32.73
  Bottom 0.254: J11.59 81.66,0.72 114.55,0.72 117.22,3.39 117.22,18.38 112.39,23.2 112.39,29.43 USB.3 | v116.2,52.67 116.58,53.05 116.58,60.8 116.45,60.92 116.5,60.97 U$41.P$3
USBD-  (via drill 0.61 pad 1.02)
  Top 0.254: USB.2 113.66,32.73 | 113.66,32.73 114.93,34 114.93,35.78 110.61,40.09 110.61,50.76 112.9,53.05 v114.68,53.05 | RUSB1.2 114.42,29.68 113.91,29.17 113.41,29.17 112.39,30.19 112.39,31.46 113.66,32.73
  Bottom 0.254: J11.60 80.89,4.03 97.66,4.03 100.07,1.49 113.91,1.49 116.45,4.03 116.45,18 111.63,23.08 111.63,30.7 USB.2 | U$41.P$4 115.82,60.92 115.82,58.76 115.95,58.64 115.95,54.32 v114.68,53.05
VCK
  Bottom 0.254: RR1.P$9 96.74,15.17 97.34,15.77 97.34,16.09 94.67,18.76 94.67,31.59 98.23,35.14 100.07,35.14 | 100.07,35.14 | 100.07,35.14 UOPT-CON.5
VIDH
  Bottom 0.254: UOPT-CON.3 98.44,36.12 93.97,31.65 93.97,28.54 93.59,28.16 91.56,28.16 90.8,28.92 90.8,35.2 88.83,37.17 87.56,37.17 86.8,36.47 86.8,36.09 86.78,36.07 RR3.P$15
VIDL  (via drill 0.51 pad 0.3)
  Top 0.254: v93.53,22.12 v99.12,22.12
  Bottom 0.254: RR3.P$16 87.28,36.19 87.75,36.66 88.58,36.66 90.23,35.01 90.23,25.43 v93.53,22.12 | UOPT-CON.31 99.13,22.12 v99.12,22.12
VOUT1
  Top 0.254: T1.P$1 59.3,28.16 59.3,26.4 | 59.3,26.4 59.3,26.38 | AMP1.1 59.3,26.4
  Top 0.61: AMP1.1 R17.2 52.32,30.95 49.93,33.36 R16.2
VOUT2
  Top 0.254: 57.78,18.76 57.91,18.76 58.03,18.76 58.29,18.5 T2.P$1 60.57,18.5
  Top 0.61: AMP1.7 57.91,18.76 58.54,18.12 58.54,16.6 R31.2 R11.2
VOUT_HI
  Top 0.254: 66.42,18 65.65,18.76 65.4,18.76 T3.P$1
  Top 0.61: R11.1 64.92,16.5 66.42,18 68.7,20.28 | 68.7,20.28 68.83,20.41 | AMP2.5 68.73,20.26 68.7,20.28
  Top 0.813: R11.1 64.89,12.79 64.87,12.94 R9.1 R10.2
VOUT_LOW
  Top 0.254: T4.P$1 64.38,29.43
  Top 0.61: R12.1 61.97,33.87 R13.2 61.97,32.47 R17.1 62.1,30.85 62.1,29.93 62.61,29.43 64.38,29.43 67.94,29.43 70.23,27.14 70.23,26.63 | 70.23,26.63 70.12,26.63 | AMP2.3 70.1,26.5 70.23,26.63
VPL
  Bottom 0.254: RR1.P$10 96.94,14.67 98.04,15.77 98.04,16.15 95.18,19.01 95.18,31.33 97.91,34.06 99.94,34.06 100.01,34.12 100.02,34.12 UOPT-CON.7
VSYNC
  Bottom 0.254: J10.23 31.87,59.14 23.24,59.14 J10.13

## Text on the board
Top: component | MIThril BSE dock v1000-5 9/04/2001
Bottom: Copyright (C) 2001 MIT Media Lab | R. W. DeVaul | mithril@media.mit.edu | EVILB0RG | borglab
tPlace: Richard W. DeVaul | MIThril@media.mit.edu | T11 | T12 | MIThril BSE dock v1000-5 9/04/2001 | Copyright (C) 2001, MIT | <borglab> | T22 | T21 | http://www.media.mit.edu/wearables/mithril/
Reference: BSE length: 3.4 in | 0.100 | 3.1 | 0.150 | 1.85 | BSE width: 2.6 in | 0.100 | 0.375
bDocu: uOpt. Cable | strain relief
